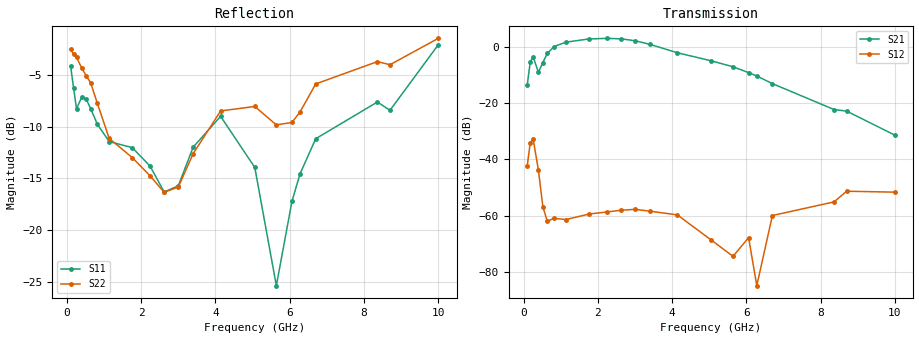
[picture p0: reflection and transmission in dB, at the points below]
! Integrated Device Technology
! Corporate Headquarters
! 6024 Silver Creek Valley Road
! San Jose, CA 95138  USA
! Phone:  1-408-284-8200
! Toll Free:  1-800-223-1366
! Webpage:  http://www.idt.com/
! Timing and RF Division
! 515 Groton Road, Suite 102
! Westford, MA 01886-6024
! Device:  F1456
! Description: 6-bit 0.5 dB Transmit Variable Gain Amplifier
! Frequency:  2100.0 -  2950.00 MHz
! Package:  6x6 mm Thin QFN Plastic Package: 28 pin
! State:  58
! Atten State:  29.0 dB
! Voltage:  +5.00 Volts
! Current:  216.944 mA
! Data:  The device was measured on a the F1455 evaluation board which has
!  individual transmission lines to the RF pins.  Data was collected
!  using a calibrated network analyzer.  The evaluation board was
!  de-embedded using a TRL calibration technique.
!  The reference plane is the edge of the package pin.
!  Pin  1 = CSb
!  Pin  2 = DATA
!  Pin  3 = CLK
!  Pin  4 = RSET
!  Pin  5 = GND
!  Pin  6 = RFIN  = Port 1
!  Pin  7 = GND
!  Pin  8 = NC
!  Pin  9 = NC
!  Pin 10 = NC
!  Pin 11 = NC
!  Pin 12 = NC
!  Pin 13 = NC
!  Pin 14 = /STBY
!  Pin 15 = GND
!  Pin 16 = RFOUT  = Port 2
!  Pin 17 = GND
!  Pin 18 = NC
!  Pin 19 = NC
!  Pin 20 = NC
!  Pin 21 = GND
!  Pin 22 = NC
!  Pin 23 = GND
!  Pin 24 = NC
!  Pin 25 = NC
!  Pin 26 = NC
!  Pin 27 = GND
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# GHz S dB R 50
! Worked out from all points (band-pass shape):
!   496 points, 100 MHz to 10 GHz, reference 50 ohm
!   highest |S21| = 2.99 dB at 2.24 GHz (marker M1); lowest = -31.4 dB at 10 GHz (marker M2)
!   |S21| within 3 dB of the highest: 812.6 MHz to 3.621 GHz (2.809 GHz wide, 127 % of centre)
!   lowest |S11| = -25.4 dB at 5.64 GHz (marker M3), VSWR 1.11, Z = 52.5 + j4.91 ohm
!   |S11| at or under -10 dB: 856.4 MHz to 3.711 GHz (2.854 GHz wide, 125 % of centre); 4.606 GHz to 6.902 GHz (2.296 GHz wide, 39.9 % of centre); 6.983 GHz to 7.061 GHz (77.88 MHz wide, 1.11 % of centre)
!   |S22| runs from -16.5 to -1.5 dB; largest |S21 - S12| = 1.4
!   S11 on the Smith chart (normalised r, x): 100 MHz: 2.37, -2.04; 640 MHz: 1.03, -0.85; 3 GHz: 0.77, +0.18; 6.06 GHz: 1.30, +0.10; 8.7 GHz: 0.90, +0.77; 10 GHz: 4.20, +4.13
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0.1  -4.10 -24.9  -13.58 -151.0  -42.29 50.5  -2.51 140.7
0.18  -6.25 -40.1  -5.46 158.4  -34.17 -2.4  -2.98 109.7
0.26  -8.27 -28.4  -3.60 59.9  -32.88 -100.5  -3.30 88.7
0.4  -7.15 -34.0  -9.11 -94.0  -43.76 149.5  -4.32 44.6
0.52  -7.34 -50.8  -5.61 164.5  -56.83 116.4  -5.07 20.2
0.64  -8.26 -65.5  -2.36 111.8  -62.03 140.4  -5.76 -7.0
0.82  -9.76 -84.0  0.06 59.5  -60.97 120.7  -7.74 -45.1
1.14  -11.45 -110.7  1.64 -0.8  -61.43 87.7  -11.14 -90.9
1.76  -12.03 -139.0  2.78 -83.7  -59.47 53.6  -12.99 -134.2
2.24  -13.82 -154.4  2.99 -137.9  -58.72 37.5  -14.76 -150.2
2.62  -16.32 180.0  2.83 -179.6  -58.12 23.7  -16.36 -167.7
3  -15.73 136.3  2.16 139.1  -57.80 6.1  -15.84 163.6
3.4  -11.99 113.5  0.88 98.4  -58.44 -9.3  -12.62 140.7
4.14  -9.00 113.1  -2.12 34.5  -59.75 -43.0  -8.48 131.1
5.06  -13.95 123.0  -5.01 -38.6  -68.76 -89.0  -8.05 137.0
5.64  -25.39 60.2  -7.11 -89.2  -74.50 167.3  -9.83 121.7
6.06  -17.23 16.5  -9.18 -128.0  -67.83 140.2  -9.60 92.4
6.28  -14.55 22.0  -10.38 -148.0  -84.93 144.9  -8.57 78.7
6.7  -11.17 40.7  -13.09 173.5  -60.00 142.7  -5.87 65.0
8.36  -7.62 88.6  -22.31 61.5  -55.14 55.5  -3.71 62.5
8.7  -8.42 75.1  -22.88 34.0  -51.35 66.8  -4.01 51.2
10  -2.08 13.8  -31.43 -71.6  -51.68 -26.8  -1.46 -2.6
